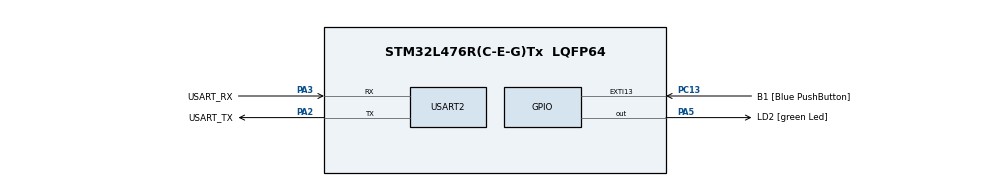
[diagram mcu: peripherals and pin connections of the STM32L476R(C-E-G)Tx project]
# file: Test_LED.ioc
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Mcu.Family=STM32L4
Mcu.Name=STM32L476R(C-E-G)Tx
Mcu.Package=LQFP64
NVIC.PriorityGroup=NVIC_PRIORITYGROUP_4
PA13\ (JTMS-SWDIO).GPIO_Label=TMS
PA13\ (JTMS-SWDIO).Mode=Serial_Wire
PA13\ (JTMS-SWDIO).Signal=SYS_JTMS-SWDIO
PA14\ (JTCK-SWCLK).GPIO_Label=TCK
PA14\ (JTCK-SWCLK).Mode=Serial_Wire
PA14\ (JTCK-SWCLK).Signal=SYS_JTCK-SWCLK
PA2.GPIO_Label=USART_TX
PA2.GPIO_Mode=GPIO_MODE_AF_PP
PA2.GPIO_PuPd=GPIO_NOPULL
PA2.GPIO_Speed=GPIO_SPEED_FREQ_VERY_HIGH
PA2.Mode=Asynchronous
PA2.Signal=USART2_TX
PA3.GPIO_Label=USART_RX
PA3.GPIO_Mode=GPIO_MODE_AF_PP
PA3.GPIO_PuPd=GPIO_NOPULL
PA3.GPIO_Speed=GPIO_SPEED_FREQ_VERY_HIGH
PA3.Mode=Asynchronous
PA3.Signal=USART2_RX
PA5.GPIO_Label=LD2 [green Led]
PA5.GPIO_ModeDefaultOutputPP=GPIO_MODE_OUTPUT_PP
PA5.GPIO_PuPd=GPIO_NOPULL
PA5.GPIO_Speed=GPIO_SPEED_FREQ_LOW
PA5.Signal=GPIO_Output
PB3\ (JTDO-TRACESWO).GPIO_Label=SWO
PB3\ (JTDO-TRACESWO).Signal=SYS_JTDO-SWO
PC13.GPIO_Label=B1 [Blue PushButton]
PC13.GPIO_ModeDefaultEXTI=GPIO_MODE_IT_FALLING
PC13.GPIO_PuPd=GPIO_NOPULL
PC13.Signal=GPXTI13
PC14-OSC32_IN\ (PC14).Mode=LSE-External-Oscillator
PC14-OSC32_IN\ (PC14).Signal=RCC_OSC32_IN
PC15-OSC32_OUT\ (PC15).Mode=LSE-External-Oscillator
PC15-OSC32_OUT\ (PC15).Signal=RCC_OSC32_OUT
PH0-OSC_IN\ (PH0).Signal=RCC_OSC_IN
PH1-OSC_OUT\ (PH1).Signal=RCC_OSC_OUT
ProjectManager.HeapSize=0x200
ProjectManager.StackSize=0x400
ProjectManager.TargetToolchain=STM32CubeIDE
RCC.ADCFreq_Value=64000000
RCC.AHBFreq_Value=80000000
RCC.APB1Freq_Value=80000000
RCC.APB1TimFreq_Value=80000000
RCC.APB2Freq_Value=80000000
RCC.APB2TimFreq_Value=80000000
RCC.CortexFreq_Value=80000000
RCC.HCLKFreq_Value=80000000
RCC.HSE_VALUE=8000000
RCC.HSI_VALUE=16000000
RCC.MSI_VALUE=4000000
RCC.PLLN=10
RCC.PLLSourceVirtual=RCC_PLLSOURCE_HSI
RCC.PREFETCH_ENABLE=1
RCC.SYSCLKFreq_VALUE=80000000
RCC.SYSCLKSource=RCC_SYSCLKSOURCE_PLLCLK
RCC.USBFreq_Value=64000000
RCC.VCOOutputFreq_Value=160000000
USART2.VirtualMode-Asynchronous=VM_ASYNC
board=NUCLEO-L476RG

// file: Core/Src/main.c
/* USER CODE BEGIN Header */
/**
  ******************************************************************************
  * @file           : main.c
  * @brief          : Main program body
  ******************************************************************************
  * @attention
  *
  * Copyright (c) 2023 STMicroelectronics.
  * All rights reserved.
  *
  * This software is licensed under terms that can be found in the LICENSE file
  * in the root directory of this software component.
  * If no LICENSE file comes with this software, it is provided AS-IS.
  *
  ******************************************************************************
  */
/* USER CODE END Header */
#include "main.h"

UART_HandleTypeDef huart2;

void SystemClock_Config(void);
static void MX_GPIO_Init(void);
static void MX_USART2_UART_Init(void);

int main(void)
{

  /* MCU Configuration--------------------------------------------------------*/

  /* Reset of all peripherals, Initializes the Flash interface and the Systick. */
  HAL_Init();

  /* Configure the system clock */
  SystemClock_Config();

  /* Initialize all configured peripherals */
  MX_GPIO_Init();
  MX_USART2_UART_Init();

  /* Infinite loop */
  while (1)
  {

  }
}

void SystemClock_Config(void)
{
  RCC_OscInitTypeDef RCC_OscInitStruct = {0};
  RCC_ClkInitTypeDef RCC_ClkInitStruct = {0};

  /** Configure the main internal regulator output voltage
  */
  if (HAL_PWREx_ControlVoltageScaling(PWR_REGULATOR_VOLTAGE_SCALE1) != HAL_OK)
  {
    Error_Handler();
  }

  /** Initializes the RCC Oscillators according to the specified parameters
  * in the RCC_OscInitTypeDef structure.
  */
  RCC_OscInitStruct.OscillatorType = RCC_OSCILLATORTYPE_HSI;
  RCC_OscInitStruct.HSIState = RCC_HSI_ON;
  RCC_OscInitStruct.HSICalibrationValue = RCC_HSICALIBRATION_DEFAULT;
  RCC_OscInitStruct.PLL.PLLState = RCC_PLL_ON;
  RCC_OscInitStruct.PLL.PLLSource = RCC_PLLSOURCE_HSI;
  RCC_OscInitStruct.PLL.PLLM = 1000;
  RCC_OscInitStruct.PLL.PLLN = 1000;
  RCC_OscInitStruct.PLL.PLLP = RCC_PLLP_DIV7;
  RCC_OscInitStruct.PLL.PLLQ = RCC_PLLQ_DIV2;
  RCC_OscInitStruct.PLL.PLLR = RCC_PLLR_DIV2;
  if (HAL_RCC_OscConfig(&RCC_OscInitStruct) != HAL_OK)
  {
    Error_Handler();
  }

  /** Initializes the CPU, AHB and APB buses clocks
  */
  RCC_ClkInitStruct.ClockType = RCC_CLOCKTYPE_HCLK|RCC_CLOCKTYPE_SYSCLK
                              |RCC_CLOCKTYPE_PCLK1|RCC_CLOCKTYPE_PCLK2;
  RCC_ClkInitStruct.SYSCLKSource = RCC_SYSCLKSOURCE_PLLCLK;
  RCC_ClkInitStruct.AHBCLKDivider = RCC_SYSCLK_DIV1;
  RCC_ClkInitStruct.APB1CLKDivider = RCC_HCLK_DIV1;
  RCC_ClkInitStruct.APB2CLKDivider = RCC_HCLK_DIV1;

  if (HAL_RCC_ClockConfig(&RCC_ClkInitStruct, FLASH_LATENCY_4) != HAL_OK)
  {
    Error_Handler();
  }
}

static void MX_USART2_UART_Init(void)
{

  huart2.Instance = USART2;
  huart2.Init.BaudRate = 115200;
  huart2.Init.WordLength = UART_WORDLENGTH_8B;
  huart2.Init.StopBits = UART_STOPBITS_1;
  huart2.Init.Parity = UART_PARITY_NONE;
  huart2.Init.Mode = UART_MODE_TX_RX;
  huart2.Init.HwFlowCtl = UART_HWCONTROL_NONE;
  huart2.Init.OverSampling = UART_OVERSAMPLING_16;
  huart2.Init.OneBitSampling = UART_ONE_BIT_SAMPLE_DISABLE;
  huart2.AdvancedInit.AdvFeatureInit = UART_ADVFEATURE_NO_INIT;
  if (HAL_UART_Init(&huart2) != HAL_OK)
  {
    Error_Handler();
  }

}

static void MX_GPIO_Init(void)
{
  GPIO_InitTypeDef GPIO_InitStruct = {0};

  /* GPIO Ports Clock Enable */
  __HAL_RCC_GPIOC_CLK_ENABLE();
  __HAL_RCC_GPIOH_CLK_ENABLE();
  __HAL_RCC_GPIOA_CLK_ENABLE();
  __HAL_RCC_GPIOB_CLK_ENABLE();

  /*Configure GPIO pin Output Level */
  HAL_GPIO_WritePin(LD2_GPIO_Port, LD2_Pin, GPIO_PIN_RESET);

  /*Configure GPIO pin : B1_Pin */
  GPIO_InitStruct.Pin = B1_Pin;
  GPIO_InitStruct.Mode = GPIO_MODE_IT_FALLING;
  GPIO_InitStruct.Pull = GPIO_NOPULL;
  HAL_GPIO_Init(B1_GPIO_Port, &GPIO_InitStruct);

  /*Configure GPIO pin : LD2_Pin */
  GPIO_InitStruct.Pin = LD2_Pin;
  GPIO_InitStruct.Mode = GPIO_MODE_OUTPUT_PP;
  GPIO_InitStruct.Pull = GPIO_NOPULL;
  GPIO_InitStruct.Speed = GPIO_SPEED_FREQ_LOW;
  HAL_GPIO_Init(LD2_GPIO_Port, &GPIO_InitStruct);

}

void Error_Handler(void)
{
  __disable_irq();
  while (1)
  {
  }
}
